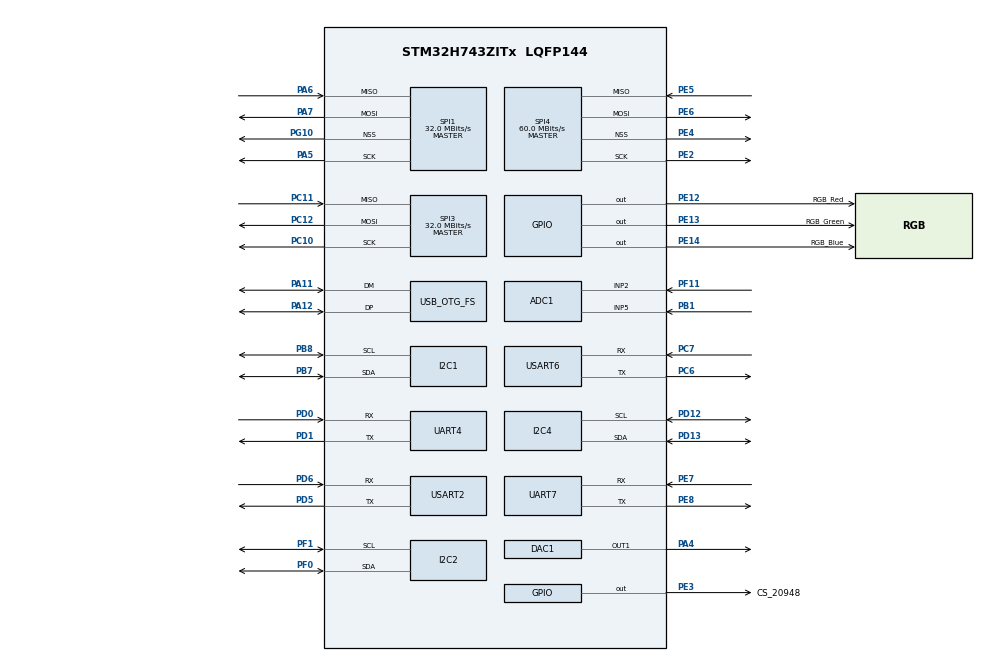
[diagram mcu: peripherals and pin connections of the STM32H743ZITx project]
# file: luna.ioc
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ADC1.Channel-3\#ChannelRegularConversion=ADC_CHANNEL_2
ADC1.NbrOfConversionFlag=1
ADC1.OffsetNumber-3\#ChannelRegularConversion=ADC_OFFSET_NONE
ADC1.OffsetSignedSaturation-3\#ChannelRegularConversion=DISABLE
ADC1.Rank-3\#ChannelRegularConversion=1
ADC1.SamplingTime-3\#ChannelRegularConversion=ADC_SAMPLETIME_1CYCLE_5
ADC1.master=1
ADC3.Channel-0\#ChannelRegularConversion=ADC_CHANNEL_VREFINT
ADC3.NbrOfConversionFlag=1
ADC3.OffsetNumber-0\#ChannelRegularConversion=ADC_OFFSET_NONE
ADC3.OffsetSignedSaturation-0\#ChannelRegularConversion=DISABLE
ADC3.Rank-0\#ChannelRegularConversion=1
ADC3.SamplingTime-0\#ChannelRegularConversion=ADC_SAMPLETIME_1CYCLE_5
DAC1.DAC_Channel-DAC_OUT1=DAC_CHANNEL_1
I2C1.Timing=0x307075B1
I2C2.Timing=0x307075B1
I2C4.Timing=0x307075B1
Mcu.Family=STM32H7
Mcu.Name=STM32H743ZITx
Mcu.Package=LQFP144
NVIC.PriorityGroup=NVIC_PRIORITYGROUP_4
PA11.Mode=Device_Only
PA11.Signal=USB_OTG_FS_DM
PA12.Mode=Device_Only
PA12.Signal=USB_OTG_FS_DP
PA13\ (JTMS/SWDIO).Mode=Trace_Asynchronous_SW
PA13\ (JTMS/SWDIO).Signal=DEBUG_JTMS-SWDIO
PA14\ (JTCK/SWCLK).Mode=Trace_Asynchronous_SW
PA14\ (JTCK/SWCLK).Signal=DEBUG_JTCK-SWCLK
PA4.Signal=COMP_DAC11_group
PA5.Mode=Full_Duplex_Master
PA5.Signal=SPI1_SCK
PA6.Mode=Full_Duplex_Master
PA6.Signal=SPI1_MISO
PA7.Mode=Full_Duplex_Master
PA7.Signal=SPI1_MOSI
PB1.Signal=ADCx_INP5
PB3\ (JTDO/TRACESWO).Mode=Trace_Asynchronous_SW
PB3\ (JTDO/TRACESWO).Signal=DEBUG_JTDO-SWO
PB7.Mode=I2C
PB7.Signal=I2C1_SDA
PB8.Mode=I2C
PB8.Signal=I2C1_SCL
PC10.Mode=Full_Duplex_Master
PC10.Signal=SPI3_SCK
PC11.Mode=Full_Duplex_Master
PC11.Signal=SPI3_MISO
PC12.Mode=Full_Duplex_Master
PC12.Signal=SPI3_MOSI
PC14-OSC32_IN\ (OSC32_IN).Mode=LSE-External-Clock-Source
PC14-OSC32_IN\ (OSC32_IN).Signal=RCC_OSC32_IN
PC6.Mode=Asynchronous
PC6.Signal=USART6_TX
PC7.Mode=Asynchronous
PC7.Signal=USART6_RX
PD0.Mode=Asynchronous
PD0.Signal=UART4_RX
PD1.Mode=Asynchronous
PD1.Signal=UART4_TX
PD12.Mode=I2C
PD12.Signal=I2C4_SCL
PD13.Mode=I2C
PD13.Signal=I2C4_SDA
PD5.Mode=Asynchronous
PD5.Signal=USART2_TX
PD6.Mode=Asynchronous
PD6.Signal=USART2_RX
PE12.GPIO_Label=RGB_Red
PE12.Signal=GPIO_Output
PE13.GPIO_Label=RGB_Green
PE13.Signal=GPIO_Output
PE14.GPIO_Label=RGB_Blue
PE14.Signal=GPIO_Output
PE2.Mode=Full_Duplex_Master
PE2.Signal=SPI4_SCK
PE3.GPIO_Label=CS_20948
PE3.Signal=GPIO_Output
PE4.Mode=NSS_Signal_Hard_Output
PE4.Signal=SPI4_NSS
PE5.Mode=Full_Duplex_Master
PE5.Signal=SPI4_MISO
PE6.Mode=Full_Duplex_Master
PE6.Signal=SPI4_MOSI
PE7.Mode=Asynchronous
PE7.Signal=UART7_RX
PE8.Mode=Asynchronous
PE8.Signal=UART7_TX
PF0.Mode=I2C
PF0.Signal=I2C2_SDA
PF1.Mode=I2C
PF1.Signal=I2C2_SCL
PF11.Mode=IN2-Single-Ended
PF11.Signal=ADC1_INP2
PG10.Mode=NSS_Signal_Hard_Output
PG10.Signal=SPI1_NSS
PH0-OSC_IN\ (PH0).Mode=HSE-External-Clock-Source
PH0-OSC_IN\ (PH0).Signal=RCC_OSC_IN
ProjectManager.HeapSize=0x200
ProjectManager.StackSize=0x400
ProjectManager.TargetToolchain=STM32CubeIDE
RCC.ADCFreq_Value=75000640.86914062
RCC.APB1Freq_Value=120000000
RCC.APB2Freq_Value=120000000
RCC.APB3Freq_Value=120000000
RCC.APB4Freq_Value=120000000
RCC.CortexFreq_Value=480000000
RCC.D1PPRE=RCC_APB3_DIV2
RCC.D2PPRE1=RCC_APB1_DIV2
RCC.D2PPRE2=RCC_APB2_DIV2
RCC.D3PPRE=RCC_APB4_DIV2
RCC.DIVM1=9
RCC.DIVM2=2
RCC.DIVN1=320
RCC.DIVN2=11
RCC.DIVQ1=15
RCC.DIVR1=3
RCC.EnableCSSLSE=true
RCC.EnbaleCSS=true
RCC.HCLKFreq_Value=240000000
RCC.HPRE=RCC_HCLK_DIV2
RCC.HSE_VALUE=27000000
RCC.PLL2FRACN=911
RCC.PLL3FRACN=0
RCC.PLLFRACN=0
RCC.RTCClockSelection=RCC_RTCCLKSOURCE_LSE
RCC.SYSCLKFreq_VALUE=480000000
RCC.SYSCLKSource=RCC_SYSCLKSOURCE_PLLCLK
RCC.USBFreq_Value=64000000
SH.ADCx_INP5.0=ADC1_INP5,IN5-Single-Ended
SH.COMP_DAC11_group.0=DAC1_OUT1,DAC_OUT1
SPI1.CalculateBaudRate=32.0 MBits/s
SPI1.Direction=SPI_DIRECTION_2LINES
SPI1.Mode=SPI_MODE_MASTER
SPI1.VirtualNSS=VM_NSSHARD
SPI1.VirtualType=VM_MASTER
SPI3.CalculateBaudRate=32.0 MBits/s
SPI3.Direction=SPI_DIRECTION_2LINES
SPI3.Mode=SPI_MODE_MASTER
SPI3.VirtualType=VM_MASTER
SPI4.CalculateBaudRate=60.0 MBits/s
SPI4.Direction=SPI_DIRECTION_2LINES
SPI4.Mode=SPI_MODE_MASTER
SPI4.VirtualNSS=VM_NSSHARD
SPI4.VirtualType=VM_MASTER
USART2.VirtualMode-Asynchronous=VM_ASYNC
USART6.VirtualMode-Asynchronous=VM_ASYNC
USB_OTG_FS.VirtualMode=Device_Only
VP_ADC3_TempSens_Input.Mode=IN-TempSens
VP_ADC3_Vref_Input.Mode=IN-Vrefint
VP_RTC_VS_RTC_Activate.Mode=RTC_Enabled
VP_TIM3_VS_ClockSourceINT.Mode=Internal
board=custom

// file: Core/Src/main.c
/* USER CODE BEGIN Header */
/**
  ******************************************************************************
  * @file           : main.c
  * @brief          : Main program body
  ******************************************************************************
  * @attention
  *
  * Copyright (c) 2024 STMicroelectronics.
  * All rights reserved.
  *
  * This software is licensed under terms that can be found in the LICENSE file
  * in the root directory of this software component.
  * If no LICENSE file comes with this software, it is provided AS-IS.
  *
  ******************************************************************************
  */
/* USER CODE END Header */
#include "main.h"

ADC_HandleTypeDef hadc1;
ADC_HandleTypeDef hadc3;

DAC_HandleTypeDef hdac1;

I2C_HandleTypeDef hi2c1;
I2C_HandleTypeDef hi2c2;
I2C_HandleTypeDef hi2c4;

RTC_HandleTypeDef hrtc;

SPI_HandleTypeDef hspi1;
SPI_HandleTypeDef hspi3;
SPI_HandleTypeDef hspi4;

TIM_HandleTypeDef htim3;

UART_HandleTypeDef huart4;
UART_HandleTypeDef huart7;
UART_HandleTypeDef huart2;
UART_HandleTypeDef huart6;

PCD_HandleTypeDef hpcd_USB_OTG_FS;

void SystemClock_Config(void);
void PeriphCommonClock_Config(void);
static void MX_GPIO_Init(void);
static void MX_RTC_Init(void);
static void MX_USB_OTG_FS_PCD_Init(void);
static void MX_ADC1_Init(void);
static void MX_DAC1_Init(void);
static void MX_I2C1_Init(void);
static void MX_I2C2_Init(void);
static void MX_I2C4_Init(void);
static void MX_SPI1_Init(void);
static void MX_SPI3_Init(void);
static void MX_TIM3_Init(void);
static void MX_SPI4_Init(void);
static void MX_UART4_Init(void);
static void MX_UART7_Init(void);
static void MX_USART2_UART_Init(void);
static void MX_USART6_UART_Init(void);
static void MX_ADC3_Init(void);

int main(void)
{

  /* MCU Configuration--------------------------------------------------------*/

  /* Reset of all peripherals, Initializes the Flash interface and the Systick. */
  HAL_Init();

  /* Configure the system clock */
  SystemClock_Config();

/* Configure the peripherals common clocks */
  PeriphCommonClock_Config();

  /* Initialize all configured peripherals */
  MX_GPIO_Init();
  MX_RTC_Init();
  MX_USB_OTG_FS_PCD_Init();
  MX_ADC1_Init();
  MX_DAC1_Init();
  MX_I2C1_Init();
  MX_I2C2_Init();
  MX_I2C4_Init();
  MX_SPI1_Init();
  MX_SPI3_Init();
  MX_TIM3_Init();
  MX_SPI4_Init();
  MX_UART4_Init();
  MX_UART7_Init();
  MX_USART2_UART_Init();
  MX_USART6_UART_Init();
  MX_ADC3_Init();

  /* Infinite loop */
  while (1)
  {

  }
}

void SystemClock_Config(void)
{
  RCC_OscInitTypeDef RCC_OscInitStruct = {0};
  RCC_ClkInitTypeDef RCC_ClkInitStruct = {0};

  /** Supply configuration update enable
  */
  HAL_PWREx_ConfigSupply(PWR_LDO_SUPPLY);

  /** Configure the main internal regulator output voltage
  */
  __HAL_PWR_VOLTAGESCALING_CONFIG(PWR_REGULATOR_VOLTAGE_SCALE3);

  while(!__HAL_PWR_GET_FLAG(PWR_FLAG_VOSRDY)) {}

  /** Initializes the RCC Oscillators according to the specified parameters
  * in the RCC_OscInitTypeDef structure.
  */
  RCC_OscInitStruct.OscillatorType = RCC_OSCILLATORTYPE_HSI|RCC_OSCILLATORTYPE_LSI
                              |RCC_OSCILLATORTYPE_HSE;
  RCC_OscInitStruct.HSEState = RCC_HSE_BYPASS;
  RCC_OscInitStruct.HSIState = RCC_HSI_DIV1;
  RCC_OscInitStruct.HSICalibrationValue = RCC_HSICALIBRATION_DEFAULT;
  RCC_OscInitStruct.LSIState = RCC_LSI_ON;
  RCC_OscInitStruct.PLL.PLLState = RCC_PLL_ON;
  RCC_OscInitStruct.PLL.PLLSource = RCC_PLLSOURCE_HSE;
  RCC_OscInitStruct.PLL.PLLM = 2;
  RCC_OscInitStruct.PLL.PLLN = 32;
  RCC_OscInitStruct.PLL.PLLP = 2;
  RCC_OscInitStruct.PLL.PLLQ = 9;
  RCC_OscInitStruct.PLL.PLLR = 3;
  RCC_OscInitStruct.PLL.PLLRGE = RCC_PLL1VCIRANGE_3;
  RCC_OscInitStruct.PLL.PLLVCOSEL = RCC_PLL1VCOWIDE;
  RCC_OscInitStruct.PLL.PLLFRACN = 0;
  if (HAL_RCC_OscConfig(&RCC_OscInitStruct) != HAL_OK)
  {
    Error_Handler();
  }

  /** Initializes the CPU, AHB and APB buses clocks
  */
  RCC_ClkInitStruct.ClockType = RCC_CLOCKTYPE_HCLK|RCC_CLOCKTYPE_SYSCLK
                              |RCC_CLOCKTYPE_PCLK1|RCC_CLOCKTYPE_PCLK2
                              |RCC_CLOCKTYPE_D3PCLK1|RCC_CLOCKTYPE_D1PCLK1;
  RCC_ClkInitStruct.SYSCLKSource = RCC_SYSCLKSOURCE_HSI;
  RCC_ClkInitStruct.SYSCLKDivider = RCC_SYSCLK_DIV1;
  RCC_ClkInitStruct.AHBCLKDivider = RCC_HCLK_DIV2;
  RCC_ClkInitStruct.APB3CLKDivider = RCC_APB3_DIV2;
  RCC_ClkInitStruct.APB1CLKDivider = RCC_APB1_DIV2;
  RCC_ClkInitStruct.APB2CLKDivider = RCC_APB2_DIV2;
  RCC_ClkInitStruct.APB4CLKDivider = RCC_APB4_DIV2;

  if (HAL_RCC_ClockConfig(&RCC_ClkInitStruct, FLASH_LATENCY_0) != HAL_OK)
  {
    Error_Handler();
  }
}

void PeriphCommonClock_Config(void)
{
  RCC_PeriphCLKInitTypeDef PeriphClkInitStruct = {0};

  /** Initializes the peripherals clock
  */
  PeriphClkInitStruct.PeriphClockSelection = RCC_PERIPHCLK_ADC;
  PeriphClkInitStruct.PLL2.PLL2M = 2;
  PeriphClkInitStruct.PLL2.PLL2N = 11;
  PeriphClkInitStruct.PLL2.PLL2P = 2;
  PeriphClkInitStruct.PLL2.PLL2Q = 2;
  PeriphClkInitStruct.PLL2.PLL2R = 2;
  PeriphClkInitStruct.PLL2.PLL2RGE = RCC_PLL2VCIRANGE_3;
  PeriphClkInitStruct.PLL2.PLL2VCOSEL = RCC_PLL2VCOMEDIUM;
  PeriphClkInitStruct.PLL2.PLL2FRACN = 911;
  PeriphClkInitStruct.AdcClockSelection = RCC_ADCCLKSOURCE_PLL2;
  if (HAL_RCCEx_PeriphCLKConfig(&PeriphClkInitStruct) != HAL_OK)
  {
    Error_Handler();
  }
}

static void MX_ADC1_Init(void)
{

  ADC_MultiModeTypeDef multimode = {0};
  ADC_ChannelConfTypeDef sConfig = {0};

  /** Common config
  */
  hadc1.Instance = ADC1;
  hadc1.Init.ClockPrescaler = ADC_CLOCK_ASYNC_DIV2;
  hadc1.Init.Resolution = ADC_RESOLUTION_16B;
  hadc1.Init.ScanConvMode = ADC_SCAN_DISABLE;
  hadc1.Init.EOCSelection = ADC_EOC_SINGLE_CONV;
  hadc1.Init.LowPowerAutoWait = DISABLE;
  hadc1.Init.ContinuousConvMode = DISABLE;
  hadc1.Init.NbrOfConversion = 1;
  hadc1.Init.DiscontinuousConvMode = DISABLE;
  hadc1.Init.ExternalTrigConv = ADC_SOFTWARE_START;
  hadc1.Init.ExternalTrigConvEdge = ADC_EXTERNALTRIGCONVEDGE_NONE;
  hadc1.Init.ConversionDataManagement = ADC_CONVERSIONDATA_DR;
  hadc1.Init.Overrun = ADC_OVR_DATA_PRESERVED;
  hadc1.Init.LeftBitShift = ADC_LEFTBITSHIFT_NONE;
  hadc1.Init.OversamplingMode = DISABLE;
  if (HAL_ADC_Init(&hadc1) != HAL_OK)
  {
    Error_Handler();
  }

  /** Configure the ADC multi-mode
  */
  multimode.Mode = ADC_MODE_INDEPENDENT;
  if (HAL_ADCEx_MultiModeConfigChannel(&hadc1, &multimode) != HAL_OK)
  {
    Error_Handler();
  }

  /** Configure Regular Channel
  */
  sConfig.Channel = ADC_CHANNEL_2;
  sConfig.Rank = ADC_REGULAR_RANK_1;
  sConfig.SamplingTime = ADC_SAMPLETIME_1CYCLE_5;
  sConfig.SingleDiff = ADC_SINGLE_ENDED;
  sConfig.OffsetNumber = ADC_OFFSET_NONE;
  sConfig.Offset = 0;
  sConfig.OffsetSignedSaturation = DISABLE;
  if (HAL_ADC_ConfigChannel(&hadc1, &sConfig) != HAL_OK)
  {
    Error_Handler();
  }

}

static void MX_ADC3_Init(void)
{

  ADC_ChannelConfTypeDef sConfig = {0};

  /** Common config
  */
  hadc3.Instance = ADC3;
  hadc3.Init.Resolution = ADC_RESOLUTION_16B;
  hadc3.Init.ScanConvMode = ADC_SCAN_DISABLE;
  hadc3.Init.EOCSelection = ADC_EOC_SINGLE_CONV;
  hadc3.Init.LowPowerAutoWait = DISABLE;
  hadc3.Init.ContinuousConvMode = DISABLE;
  hadc3.Init.NbrOfConversion = 1;
  hadc3.Init.DiscontinuousConvMode = DISABLE;
  hadc3.Init.ExternalTrigConv = ADC_SOFTWARE_START;
  hadc3.Init.ExternalTrigConvEdge = ADC_EXTERNALTRIGCONVEDGE_NONE;
  hadc3.Init.ConversionDataManagement = ADC_CONVERSIONDATA_DR;
  hadc3.Init.Overrun = ADC_OVR_DATA_PRESERVED;
  hadc3.Init.LeftBitShift = ADC_LEFTBITSHIFT_NONE;
  hadc3.Init.OversamplingMode = DISABLE;
  if (HAL_ADC_Init(&hadc3) != HAL_OK)
  {
    Error_Handler();
  }

  /** Configure Regular Channel
  */
  sConfig.Channel = ADC_CHANNEL_VREFINT;
  sConfig.Rank = ADC_REGULAR_RANK_1;
  sConfig.SamplingTime = ADC_SAMPLETIME_1CYCLE_5;
  sConfig.SingleDiff = ADC_SINGLE_ENDED;
  sConfig.OffsetNumber = ADC_OFFSET_NONE;
  sConfig.Offset = 0;
  sConfig.OffsetSignedSaturation = DISABLE;
  if (HAL_ADC_ConfigChannel(&hadc3, &sConfig) != HAL_OK)
  {
    Error_Handler();
  }

}

static void MX_DAC1_Init(void)
{

  DAC_ChannelConfTypeDef sConfig = {0};

  /** DAC Initialization
  */
  hdac1.Instance = DAC1;
  if (HAL_DAC_Init(&hdac1) != HAL_OK)
  {
    Error_Handler();
  }

  /** DAC channel OUT1 config
  */
  sConfig.DAC_SampleAndHold = DAC_SAMPLEANDHOLD_DISABLE;
  sConfig.DAC_Trigger = DAC_TRIGGER_NONE;
  sConfig.DAC_OutputBuffer = DAC_OUTPUTBUFFER_ENABLE;
  sConfig.DAC_ConnectOnChipPeripheral = DAC_CHIPCONNECT_DISABLE;
  sConfig.DAC_UserTrimming = DAC_TRIMMING_FACTORY;
  if (HAL_DAC_ConfigChannel(&hdac1, &sConfig, DAC_CHANNEL_1) != HAL_OK)
  {
    Error_Handler();
  }

}

static void MX_I2C1_Init(void)
{

  hi2c1.Instance = I2C1;
  hi2c1.Init.Timing = 0x00303D5B;
  hi2c1.Init.OwnAddress1 = 0;
  hi2c1.Init.AddressingMode = I2C_ADDRESSINGMODE_7BIT;
  hi2c1.Init.DualAddressMode = I2C_DUALADDRESS_DISABLE;
  hi2c1.Init.OwnAddress2 = 0;
  hi2c1.Init.OwnAddress2Masks = I2C_OA2_NOMASK;
  hi2c1.Init.GeneralCallMode = I2C_GENERALCALL_DISABLE;
  hi2c1.Init.NoStretchMode = I2C_NOSTRETCH_DISABLE;
  if (HAL_I2C_Init(&hi2c1) != HAL_OK)
  {
    Error_Handler();
  }

  /** Configure Analogue filter
  */
  if (HAL_I2CEx_ConfigAnalogFilter(&hi2c1, I2C_ANALOGFILTER_ENABLE) != HAL_OK)
  {
    Error_Handler();
  }

  /** Configure Digital filter
  */
  if (HAL_I2CEx_ConfigDigitalFilter(&hi2c1, 0) != HAL_OK)
  {
    Error_Handler();
  }

}

static void MX_I2C2_Init(void)
{

  hi2c2.Instance = I2C2;
  hi2c2.Init.Timing = 0x00303D5B;
  hi2c2.Init.OwnAddress1 = 0;
  hi2c2.Init.AddressingMode = I2C_ADDRESSINGMODE_7BIT;
  hi2c2.Init.DualAddressMode = I2C_DUALADDRESS_DISABLE;
  hi2c2.Init.OwnAddress2 = 0;
  hi2c2.Init.OwnAddress2Masks = I2C_OA2_NOMASK;
  hi2c2.Init.GeneralCallMode = I2C_GENERALCALL_DISABLE;
  hi2c2.Init.NoStretchMode = I2C_NOSTRETCH_DISABLE;
  if (HAL_I2C_Init(&hi2c2) != HAL_OK)
  {
    Error_Handler();
  }

  /** Configure Analogue filter
  */
  if (HAL_I2CEx_ConfigAnalogFilter(&hi2c2, I2C_ANALOGFILTER_ENABLE) != HAL_OK)
  {
    Error_Handler();
  }

  /** Configure Digital filter
  */
  if (HAL_I2CEx_ConfigDigitalFilter(&hi2c2, 0) != HAL_OK)
  {
    Error_Handler();
  }

}

static void MX_I2C4_Init(void)
{

  hi2c4.Instance = I2C4;
  hi2c4.Init.Timing = 0x00303D5B;
  hi2c4.Init.OwnAddress1 = 0;
  hi2c4.Init.AddressingMode = I2C_ADDRESSINGMODE_7BIT;
  hi2c4.Init.DualAddressMode = I2C_DUALADDRESS_DISABLE;
  hi2c4.Init.OwnAddress2 = 0;
  hi2c4.Init.OwnAddress2Masks = I2C_OA2_NOMASK;
  hi2c4.Init.GeneralCallMode = I2C_GENERALCALL_DISABLE;
  hi2c4.Init.NoStretchMode = I2C_NOSTRETCH_DISABLE;
  if (HAL_I2C_Init(&hi2c4) != HAL_OK)
  {
    Error_Handler();
  }

  /** Configure Analogue filter
  */
  if (HAL_I2CEx_ConfigAnalogFilter(&hi2c4, I2C_ANALOGFILTER_ENABLE) != HAL_OK)
  {
    Error_Handler();
  }

  /** Configure Digital filter
  */
  if (HAL_I2CEx_ConfigDigitalFilter(&hi2c4, 0) != HAL_OK)
  {
    Error_Handler();
  }

}

static void MX_RTC_Init(void)
{

  /** Initialize RTC Only
  */
  hrtc.Instance = RTC;
  hrtc.Init.HourFormat = RTC_HOURFORMAT_24;
  hrtc.Init.AsynchPrediv = 127;
  hrtc.Init.SynchPrediv = 255;
  hrtc.Init.OutPut = RTC_OUTPUT_DISABLE;
  hrtc.Init.OutPutPolarity = RTC_OUTPUT_POLARITY_HIGH;
  hrtc.Init.OutPutType = RTC_OUTPUT_TYPE_OPENDRAIN;
  hrtc.Init.OutPutRemap = RTC_OUTPUT_REMAP_NONE;
  if (HAL_RTC_Init(&hrtc) != HAL_OK)
  {
    Error_Handler();
  }

}

static void MX_SPI1_Init(void)
{

  /* SPI1 parameter configuration*/
  hspi1.Instance = SPI1;
  hspi1.Init.Mode = SPI_MODE_MASTER;
  hspi1.Init.Direction = SPI_DIRECTION_2LINES;
  hspi1.Init.DataSize = SPI_DATASIZE_4BIT;
  hspi1.Init.CLKPolarity = SPI_POLARITY_LOW;
  hspi1.Init.CLKPhase = SPI_PHASE_1EDGE;
  hspi1.Init.NSS = SPI_NSS_HARD_OUTPUT;
  hspi1.Init.BaudRatePrescaler = SPI_BAUDRATEPRESCALER_2;
  hspi1.Init.FirstBit = SPI_FIRSTBIT_MSB;
  hspi1.Init.TIMode = SPI_TIMODE_DISABLE;
  hspi1.Init.CRCCalculation = SPI_CRCCALCULATION_DISABLE;
  hspi1.Init.CRCPolynomial = 0x0;
  hspi1.Init.NSSPMode = SPI_NSS_PULSE_ENABLE;
  hspi1.Init.NSSPolarity = SPI_NSS_POLARITY_LOW;
  hspi1.Init.FifoThreshold = SPI_FIFO_THRESHOLD_01DATA;
  hspi1.Init.TxCRCInitializationPattern = SPI_CRC_INITIALIZATION_ALL_ZERO_PATTERN;
  hspi1.Init.RxCRCInitializationPattern = SPI_CRC_INITIALIZATION_ALL_ZERO_PATTERN;
  hspi1.Init.MasterSSIdleness = SPI_MASTER_SS_IDLENESS_00CYCLE;
  hspi1.Init.MasterInterDataIdleness = SPI_MASTER_INTERDATA_IDLENESS_00CYCLE;
  hspi1.Init.MasterReceiverAutoSusp = SPI_MASTER_RX_AUTOSUSP_DISABLE;
  hspi1.Init.MasterKeepIOState = SPI_MASTER_KEEP_IO_STATE_DISABLE;
  hspi1.Init.IOSwap = SPI_IO_SWAP_DISABLE;
  if (HAL_SPI_Init(&hspi1) != HAL_OK)
  {
    Error_Handler();
  }

}

static void MX_SPI3_Init(void)
{

  /* SPI3 parameter configuration*/
  hspi3.Instance = SPI3;
  hspi3.Init.Mode = SPI_MODE_MASTER;
  hspi3.Init.Direction = SPI_DIRECTION_2LINES;
  hspi3.Init.DataSize = SPI_DATASIZE_4BIT;
  hspi3.Init.CLKPolarity = SPI_POLARITY_LOW;
  hspi3.Init.CLKPhase = SPI_PHASE_1EDGE;
  hspi3.Init.NSS = SPI_NSS_SOFT;
  hspi3.Init.BaudRatePrescaler = SPI_BAUDRATEPRESCALER_2;
  hspi3.Init.FirstBit = SPI_FIRSTBIT_MSB;
  hspi3.Init.TIMode = SPI_TIMODE_DISABLE;
  hspi3.Init.CRCCalculation = SPI_CRCCALCULATION_DISABLE;
  hspi3.Init.CRCPolynomial = 0x0;
  hspi3.Init.NSSPMode = SPI_NSS_PULSE_ENABLE;
  hspi3.Init.NSSPolarity = SPI_NSS_POLARITY_LOW;
  hspi3.Init.FifoThreshold = SPI_FIFO_THRESHOLD_01DATA;
  hspi3.Init.TxCRCInitializationPattern = SPI_CRC_INITIALIZATION_ALL_ZERO_PATTERN;
  hspi3.Init.RxCRCInitializationPattern = SPI_CRC_INITIALIZATION_ALL_ZERO_PATTERN;
  hspi3.Init.MasterSSIdleness = SPI_MASTER_SS_IDLENESS_00CYCLE;
  hspi3.Init.MasterInterDataIdleness = SPI_MASTER_INTERDATA_IDLENESS_00CYCLE;
  hspi3.Init.MasterReceiverAutoSusp = SPI_MASTER_RX_AUTOSUSP_DISABLE;
  hspi3.Init.MasterKeepIOState = SPI_MASTER_KEEP_IO_STATE_DISABLE;
  hspi3.Init.IOSwap = SPI_IO_SWAP_DISABLE;
  if (HAL_SPI_Init(&hspi3) != HAL_OK)
  {
    Error_Handler();
  }

}

static void MX_SPI4_Init(void)
{

  /* SPI4 parameter configuration*/
  hspi4.Instance = SPI4;
  hspi4.Init.Mode = SPI_MODE_MASTER;
  hspi4.Init.Direction = SPI_DIRECTION_2LINES;
  hspi4.Init.DataSize = SPI_DATASIZE_4BIT;
  hspi4.Init.CLKPolarity = SPI_POLARITY_LOW;
  hspi4.Init.CLKPhase = SPI_PHASE_1EDGE;
  hspi4.Init.NSS = SPI_NSS_HARD_OUTPUT;
  hspi4.Init.BaudRatePrescaler = SPI_BAUDRATEPRESCALER_2;
  hspi4.Init.FirstBit = SPI_FIRSTBIT_MSB;
  hspi4.Init.TIMode = SPI_TIMODE_DISABLE;
  hspi4.Init.CRCCalculation = SPI_CRCCALCULATION_DISABLE;
  hspi4.Init.CRCPolynomial = 0x0;
  hspi4.Init.NSSPMode = SPI_NSS_PULSE_ENABLE;
  hspi4.Init.NSSPolarity = SPI_NSS_POLARITY_LOW;
  hspi4.Init.FifoThreshold = SPI_FIFO_THRESHOLD_01DATA;
  hspi4.Init.TxCRCInitializationPattern = SPI_CRC_INITIALIZATION_ALL_ZERO_PATTERN;
  hspi4.Init.RxCRCInitializationPattern = SPI_CRC_INITIALIZATION_ALL_ZERO_PATTERN;
  hspi4.Init.MasterSSIdleness = SPI_MASTER_SS_IDLENESS_00CYCLE;
  hspi4.Init.MasterInterDataIdleness = SPI_MASTER_INTERDATA_IDLENESS_00CYCLE;
  hspi4.Init.MasterReceiverAutoSusp = SPI_MASTER_RX_AUTOSUSP_DISABLE;
  hspi4.Init.MasterKeepIOState = SPI_MASTER_KEEP_IO_STATE_DISABLE;
  hspi4.Init.IOSwap = SPI_IO_SWAP_DISABLE;
  if (HAL_SPI_Init(&hspi4) != HAL_OK)
  {
    Error_Handler();
  }

}

static void MX_TIM3_Init(void)
{

  TIM_ClockConfigTypeDef sClockSourceConfig = {0};
  TIM_MasterConfigTypeDef sMasterConfig = {0};

  htim3.Instance = TIM3;
  htim3.Init.Prescaler = 0;
  htim3.Init.CounterMode = TIM_COUNTERMODE_UP;
  htim3.Init.Period = 65535;
  htim3.Init.ClockDivision = TIM_CLOCKDIVISION_DIV1;
  htim3.Init.AutoReloadPreload = TIM_AUTORELOAD_PRELOAD_DISABLE;
  if (HAL_TIM_Base_Init(&htim3) != HAL_OK)
  {
    Error_Handler();
  }
  sClockSourceConfig.ClockSource = TIM_CLOCKSOURCE_INTERNAL;
  if (HAL_TIM_ConfigClockSource(&htim3, &sClockSourceConfig) != HAL_OK)
  {
    Error_Handler();
  }
  sMasterConfig.MasterOutputTrigger = TIM_TRGO_RESET;
  sMasterConfig.MasterSlaveMode = TIM_MASTERSLAVEMODE_DISABLE;
  if (HAL_TIMEx_MasterConfigSynchronization(&htim3, &sMasterConfig) != HAL_OK)
  {
    Error_Handler();
  }

}

static void MX_UART4_Init(void)
{

  huart4.Instance = UART4;
  huart4.Init.BaudRate = 115200;
  huart4.Init.WordLength = UART_WORDLENGTH_8B;
  huart4.Init.StopBits = UART_STOPBITS_1;
  huart4.Init.Parity = UART_PARITY_NONE;
  huart4.Init.Mode = UART_MODE_TX_RX;
  huart4.Init.HwFlowCtl = UART_HWCONTROL_NONE;
  huart4.Init.OverSampling = UART_OVERSAMPLING_16;
  huart4.Init.OneBitSampling = UART_ONE_BIT_SAMPLE_DISABLE;
  huart4.Init.ClockPrescaler = UART_PRESCALER_DIV1;
  huart4.AdvancedInit.AdvFeatureInit = UART_ADVFEATURE_NO_INIT;
  if (HAL_UART_Init(&huart4) != HAL_OK)
  {
    Error_Handler();
  }
  if (HAL_UARTEx_SetTxFifoThreshold(&huart4, UART_TXFIFO_THRESHOLD_1_8) != HAL_OK)
  {
    Error_Handler();
  }
  if (HAL_UARTEx_SetRxFifoThreshold(&huart4, UART_RXFIFO_THRESHOLD_1_8) != HAL_OK)
  {
    Error_Handler();
  }
  if (HAL_UARTEx_DisableFifoMode(&huart4) != HAL_OK)
  {
    Error_Handler();
  }

}

static void MX_UART7_Init(void)
{

  huart7.Instance = UART7;
  huart7.Init.BaudRate = 115200;
  huart7.Init.WordLength = UART_WORDLENGTH_8B;
  huart7.Init.StopBits = UART_STOPBITS_1;
  huart7.Init.Parity = UART_PARITY_NONE;
  huart7.Init.Mode = UART_MODE_TX_RX;
  huart7.Init.HwFlowCtl = UART_HWCONTROL_NONE;
  huart7.Init.OverSampling = UART_OVERSAMPLING_16;
  huart7.Init.OneBitSampling = UART_ONE_BIT_SAMPLE_DISABLE;
  huart7.Init.ClockPrescaler = UART_PRESCALER_DIV1;
  huart7.AdvancedInit.AdvFeatureInit = UART_ADVFEATURE_NO_INIT;
  if (HAL_UART_Init(&huart7) != HAL_OK)
  {
    Error_Handler();
  }
  if (HAL_UARTEx_SetTxFifoThreshold(&huart7, UART_TXFIFO_THRESHOLD_1_8) != HAL_OK)
  {
    Error_Handler();
  }
  if (HAL_UARTEx_SetRxFifoThreshold(&huart7, UART_RXFIFO_THRESHOLD_1_8) != HAL_OK)
  {
    Error_Handler();
  }
  if (HAL_UARTEx_DisableFifoMode(&huart7) != HAL_OK)
  {
    Error_Handler();
  }

}

static void MX_USART2_UART_Init(void)
{

  huart2.Instance = USART2;
  huart2.Init.BaudRate = 115200;
  huart2.Init.WordLength = UART_WORDLENGTH_8B;
  huart2.Init.StopBits = UART_STOPBITS_1;
  huart2.Init.Parity = UART_PARITY_NONE;
  huart2.Init.Mode = UART_MODE_TX_RX;
  huart2.Init.HwFlowCtl = UART_HWCONTROL_NONE;
  huart2.Init.OverSampling = UART_OVERSAMPLING_16;
  huart2.Init.OneBitSampling = UART_ONE_BIT_SAMPLE_DISABLE;
  huart2.Init.ClockPrescaler = UART_PRESCALER_DIV1;
  huart2.AdvancedInit.AdvFeatureInit = UART_ADVFEATURE_NO_INIT;
  if (HAL_UART_Init(&huart2) != HAL_OK)
  {
    Error_Handler();
  }
  if (HAL_UARTEx_SetTxFifoThreshold(&huart2, UART_TXFIFO_THRESHOLD_1_8) != HAL_OK)
  {
    Error_Handler();
  }
  if (HAL_UARTEx_SetRxFifoThreshold(&huart2, UART_RXFIFO_THRESHOLD_1_8) != HAL_OK)
  {
    Error_Handler();
  }
  if (HAL_UARTEx_DisableFifoMode(&huart2) != HAL_OK)
  {
    Error_Handler();
  }

}

static void MX_USART6_UART_Init(void)
{

  huart6.Instance = USART6;
  huart6.Init.BaudRate = 115200;
  huart6.Init.WordLength = UART_WORDLENGTH_8B;
  huart6.Init.StopBits = UART_STOPBITS_1;
  huart6.Init.Parity = UART_PARITY_NONE;
  huart6.Init.Mode = UART_MODE_TX_RX;
  huart6.Init.HwFlowCtl = UART_HWCONTROL_NONE;
  huart6.Init.OverSampling = UART_OVERSAMPLING_16;
  huart6.Init.OneBitSampling = UART_ONE_BIT_SAMPLE_DISABLE;
  huart6.Init.ClockPrescaler = UART_PRESCALER_DIV1;
  huart6.AdvancedInit.AdvFeatureInit = UART_ADVFEATURE_NO_INIT;
  if (HAL_UART_Init(&huart6) != HAL_OK)
  {
    Error_Handler();
  }
  if (HAL_UARTEx_SetTxFifoThreshold(&huart6, UART_TXFIFO_THRESHOLD_1_8) != HAL_OK)
  {
    Error_Handler();
  }
  if (HAL_UARTEx_SetRxFifoThreshold(&huart6, UART_RXFIFO_THRESHOLD_1_8) != HAL_OK)
  {
    Error_Handler();
  }
  if (HAL_UARTEx_DisableFifoMode(&huart6) != HAL_OK)
  {
    Error_Handler();
  }

}

static void MX_USB_OTG_FS_PCD_Init(void)
{

  hpcd_USB_OTG_FS.Instance = USB_OTG_FS;
  hpcd_USB_OTG_FS.Init.dev_endpoints = 9;
  hpcd_USB_OTG_FS.Init.speed = PCD_SPEED_FULL;
  hpcd_USB_OTG_FS.Init.dma_enable = DISABLE;
  hpcd_USB_OTG_FS.Init.phy_itface = PCD_PHY_EMBEDDED;
  hpcd_USB_OTG_FS.Init.Sof_enable = DISABLE;
  hpcd_USB_OTG_FS.Init.low_power_enable = DISABLE;
  hpcd_USB_OTG_FS.Init.lpm_enable = DISABLE;
  hpcd_USB_OTG_FS.Init.battery_charging_enable = DISABLE;
  hpcd_USB_OTG_FS.Init.vbus_sensing_enable = DISABLE;
  hpcd_USB_OTG_FS.Init.use_dedicated_ep1 = DISABLE;
  if (HAL_PCD_Init(&hpcd_USB_OTG_FS) != HAL_OK)
  {
    Error_Handler();
  }

}

static void MX_GPIO_Init(void)
{
  GPIO_InitTypeDef GPIO_InitStruct = {0};

  /* GPIO Ports Clock Enable */
  __HAL_RCC_GPIOE_CLK_ENABLE();
  __HAL_RCC_GPIOC_CLK_ENABLE();
  __HAL_RCC_GPIOF_CLK_ENABLE();
  __HAL_RCC_GPIOH_CLK_ENABLE();
  __HAL_RCC_GPIOA_CLK_ENABLE();
  __HAL_RCC_GPIOB_CLK_ENABLE();
  __HAL_RCC_GPIOD_CLK_ENABLE();
  __HAL_RCC_GPIOG_CLK_ENABLE();

  /*Configure GPIO pin Output Level */
  HAL_GPIO_WritePin(GPIOE, CS_20948_Pin|RGB_Red_Pin|RGB_Green_Pin|RGB_Blue_Pin, GPIO_PIN_RESET);

  /*Configure GPIO pins : CS_20948_Pin RGB_Red_Pin RGB_Green_Pin RGB_Blue_Pin */
  GPIO_InitStruct.Pin = CS_20948_Pin|RGB_Red_Pin|RGB_Green_Pin|RGB_Blue_Pin;
  GPIO_InitStruct.Mode = GPIO_MODE_OUTPUT_PP;
  GPIO_InitStruct.Pull = GPIO_NOPULL;
  GPIO_InitStruct.Speed = GPIO_SPEED_FREQ_LOW;
  HAL_GPIO_Init(GPIOE, &GPIO_InitStruct);

}

void Error_Handler(void)
{
  __disable_irq();
  while (1)
  {
  }
}
